VERSION 5.7 ;
BUSBITCHARS "[]" ;
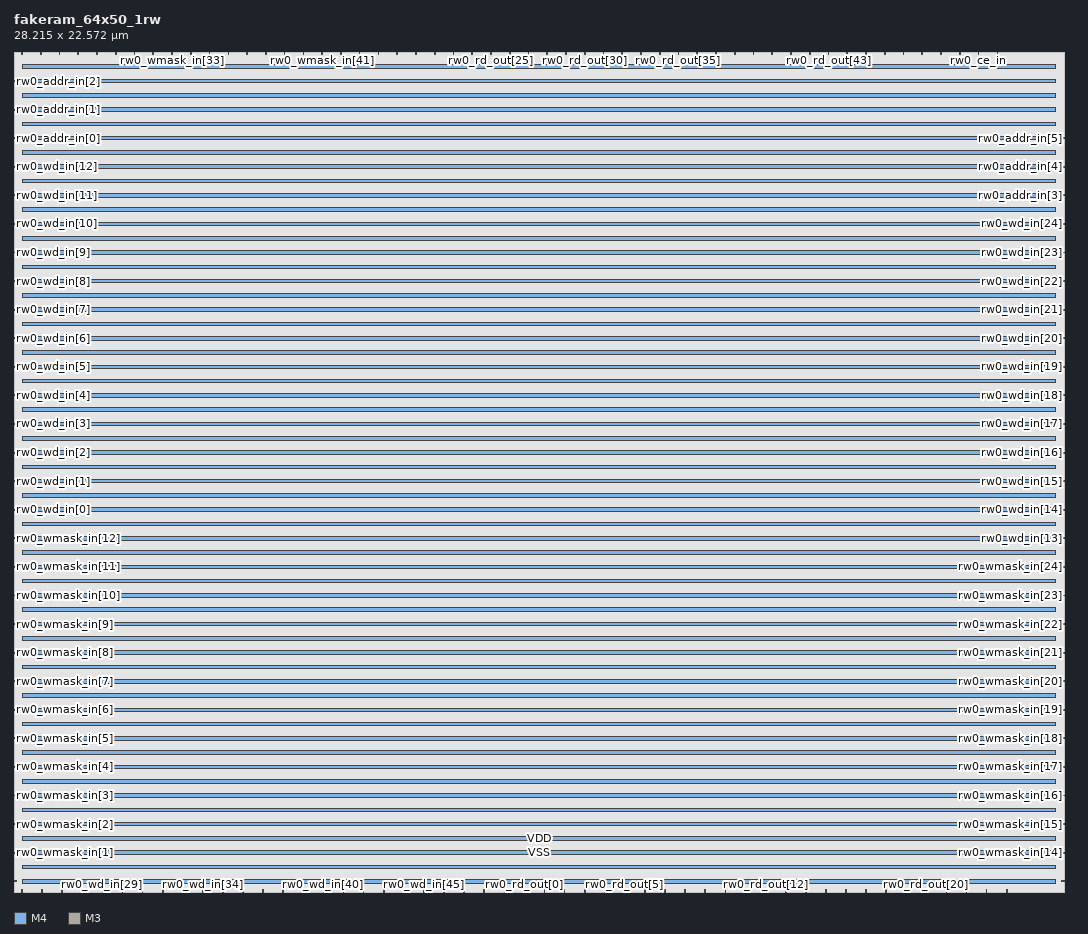
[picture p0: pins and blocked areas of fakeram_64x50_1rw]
MACRO fakeram_64x50_1rw
  FOREIGN fakeram_64x50_1rw 0 0 ;
  SYMMETRY X Y R90 ;
  SIZE 28.215 BY 22.572 ;
  CLASS BLOCK ;
  PIN rw0_wmask_in[0]
    DIRECTION INPUT ;
    USE SIGNAL ;
    SHAPE ABUTMENT ;
    PORT
      LAYER M4 ;
      RECT 0.000 0.276 0.072 0.300 ;
    END
  END rw0_wmask_in[0]
  PIN rw0_wmask_in[1]
    DIRECTION INPUT ;
    USE SIGNAL ;
    SHAPE ABUTMENT ;
    PORT
      LAYER M4 ;
      RECT 0.000 1.044 0.072 1.068 ;
    END
  END rw0_wmask_in[1]
  PIN rw0_wmask_in[2]
    DIRECTION INPUT ;
    USE SIGNAL ;
    SHAPE ABUTMENT ;
    PORT
      LAYER M4 ;
      RECT 0.000 1.812 0.072 1.836 ;
    END
  END rw0_wmask_in[2]
  PIN rw0_wmask_in[3]
    DIRECTION INPUT ;
    USE SIGNAL ;
    SHAPE ABUTMENT ;
    PORT
      LAYER M4 ;
      RECT 0.000 2.580 0.072 2.604 ;
    END
  END rw0_wmask_in[3]
  PIN rw0_wmask_in[4]
    DIRECTION INPUT ;
    USE SIGNAL ;
    SHAPE ABUTMENT ;
    PORT
      LAYER M4 ;
      RECT 0.000 3.348 0.072 3.372 ;
    END
  END rw0_wmask_in[4]
  PIN rw0_wmask_in[5]
    DIRECTION INPUT ;
    USE SIGNAL ;
    SHAPE ABUTMENT ;
    PORT
      LAYER M4 ;
      RECT 0.000 4.116 0.072 4.140 ;
    END
  END rw0_wmask_in[5]
  PIN rw0_wmask_in[6]
    DIRECTION INPUT ;
    USE SIGNAL ;
    SHAPE ABUTMENT ;
    PORT
      LAYER M4 ;
      RECT 0.000 4.884 0.072 4.908 ;
    END
  END rw0_wmask_in[6]
  PIN rw0_wmask_in[7]
    DIRECTION INPUT ;
    USE SIGNAL ;
    SHAPE ABUTMENT ;
    PORT
      LAYER M4 ;
      RECT 0.000 5.652 0.072 5.676 ;
    END
  END rw0_wmask_in[7]
  PIN rw0_wmask_in[8]
    DIRECTION INPUT ;
    USE SIGNAL ;
    SHAPE ABUTMENT ;
    PORT
      LAYER M4 ;
      RECT 0.000 6.420 0.072 6.444 ;
    END
  END rw0_wmask_in[8]
  PIN rw0_wmask_in[9]
    DIRECTION INPUT ;
    USE SIGNAL ;
    SHAPE ABUTMENT ;
    PORT
      LAYER M4 ;
      RECT 0.000 7.188 0.072 7.212 ;
    END
  END rw0_wmask_in[9]
  PIN rw0_wmask_in[10]
    DIRECTION INPUT ;
    USE SIGNAL ;
    SHAPE ABUTMENT ;
    PORT
      LAYER M4 ;
      RECT 0.000 7.956 0.072 7.980 ;
    END
  END rw0_wmask_in[10]
  PIN rw0_wmask_in[11]
    DIRECTION INPUT ;
    USE SIGNAL ;
    SHAPE ABUTMENT ;
    PORT
      LAYER M4 ;
      RECT 0.000 8.724 0.072 8.748 ;
    END
  END rw0_wmask_in[11]
  PIN rw0_wmask_in[12]
    DIRECTION INPUT ;
    USE SIGNAL ;
    SHAPE ABUTMENT ;
    PORT
      LAYER M4 ;
      RECT 0.000 9.492 0.072 9.516 ;
    END
  END rw0_wmask_in[12]
  PIN rw0_wmask_in[13]
    DIRECTION INPUT ;
    USE SIGNAL ;
    SHAPE ABUTMENT ;
    PORT
      LAYER M4 ;
      RECT 28.143 0.276 28.215 0.300 ;
    END
  END rw0_wmask_in[13]
  PIN rw0_wmask_in[14]
    DIRECTION INPUT ;
    USE SIGNAL ;
    SHAPE ABUTMENT ;
    PORT
      LAYER M4 ;
      RECT 28.143 1.044 28.215 1.068 ;
    END
  END rw0_wmask_in[14]
  PIN rw0_wmask_in[15]
    DIRECTION INPUT ;
    USE SIGNAL ;
    SHAPE ABUTMENT ;
    PORT
      LAYER M4 ;
      RECT 28.143 1.812 28.215 1.836 ;
    END
  END rw0_wmask_in[15]
  PIN rw0_wmask_in[16]
    DIRECTION INPUT ;
    USE SIGNAL ;
    SHAPE ABUTMENT ;
    PORT
      LAYER M4 ;
      RECT 28.143 2.580 28.215 2.604 ;
    END
  END rw0_wmask_in[16]
  PIN rw0_wmask_in[17]
    DIRECTION INPUT ;
    USE SIGNAL ;
    SHAPE ABUTMENT ;
    PORT
      LAYER M4 ;
      RECT 28.143 3.348 28.215 3.372 ;
    END
  END rw0_wmask_in[17]
  PIN rw0_wmask_in[18]
    DIRECTION INPUT ;
    USE SIGNAL ;
    SHAPE ABUTMENT ;
    PORT
      LAYER M4 ;
      RECT 28.143 4.116 28.215 4.140 ;
    END
  END rw0_wmask_in[18]
  PIN rw0_wmask_in[19]
    DIRECTION INPUT ;
    USE SIGNAL ;
    SHAPE ABUTMENT ;
    PORT
      LAYER M4 ;
      RECT 28.143 4.884 28.215 4.908 ;
    END
  END rw0_wmask_in[19]
  PIN rw0_wmask_in[20]
    DIRECTION INPUT ;
    USE SIGNAL ;
    SHAPE ABUTMENT ;
    PORT
      LAYER M4 ;
      RECT 28.143 5.652 28.215 5.676 ;
    END
  END rw0_wmask_in[20]
  PIN rw0_wmask_in[21]
    DIRECTION INPUT ;
    USE SIGNAL ;
    SHAPE ABUTMENT ;
    PORT
      LAYER M4 ;
      RECT 28.143 6.420 28.215 6.444 ;
    END
  END rw0_wmask_in[21]
  PIN rw0_wmask_in[22]
    DIRECTION INPUT ;
    USE SIGNAL ;
    SHAPE ABUTMENT ;
    PORT
      LAYER M4 ;
      RECT 28.143 7.188 28.215 7.212 ;
    END
  END rw0_wmask_in[22]
  PIN rw0_wmask_in[23]
    DIRECTION INPUT ;
    USE SIGNAL ;
    SHAPE ABUTMENT ;
    PORT
      LAYER M4 ;
      RECT 28.143 7.956 28.215 7.980 ;
    END
  END rw0_wmask_in[23]
  PIN rw0_wmask_in[24]
    DIRECTION INPUT ;
    USE SIGNAL ;
    SHAPE ABUTMENT ;
    PORT
      LAYER M4 ;
      RECT 28.143 8.724 28.215 8.748 ;
    END
  END rw0_wmask_in[24]
  PIN rw0_wmask_in[25]
    DIRECTION INPUT ;
    USE SIGNAL ;
    SHAPE ABUTMENT ;
    PORT
      LAYER M3 ;
      RECT 0.207 22.518 0.225 22.572 ;
    END
  END rw0_wmask_in[25]
  PIN rw0_wmask_in[26]
    DIRECTION INPUT ;
    USE SIGNAL ;
    SHAPE ABUTMENT ;
    PORT
      LAYER M3 ;
      RECT 0.711 22.518 0.729 22.572 ;
    END
  END rw0_wmask_in[26]
  PIN rw0_wmask_in[27]
    DIRECTION INPUT ;
    USE SIGNAL ;
    SHAPE ABUTMENT ;
    PORT
      LAYER M3 ;
      RECT 1.215 22.518 1.233 22.572 ;
    END
  END rw0_wmask_in[27]
  PIN rw0_wmask_in[28]
    DIRECTION INPUT ;
    USE SIGNAL ;
    SHAPE ABUTMENT ;
    PORT
      LAYER M3 ;
      RECT 1.719 22.518 1.737 22.572 ;
    END
  END rw0_wmask_in[28]
  PIN rw0_wmask_in[29]
    DIRECTION INPUT ;
    USE SIGNAL ;
    SHAPE ABUTMENT ;
    PORT
      LAYER M3 ;
      RECT 2.223 22.518 2.241 22.572 ;
    END
  END rw0_wmask_in[29]
  PIN rw0_wmask_in[30]
    DIRECTION INPUT ;
    USE SIGNAL ;
    SHAPE ABUTMENT ;
    PORT
      LAYER M3 ;
      RECT 2.727 22.518 2.745 22.572 ;
    END
  END rw0_wmask_in[30]
  PIN rw0_wmask_in[31]
    DIRECTION INPUT ;
    USE SIGNAL ;
    SHAPE ABUTMENT ;
    PORT
      LAYER M3 ;
      RECT 3.231 22.518 3.249 22.572 ;
    END
  END rw0_wmask_in[31]
  PIN rw0_wmask_in[32]
    DIRECTION INPUT ;
    USE SIGNAL ;
    SHAPE ABUTMENT ;
    PORT
      LAYER M3 ;
      RECT 3.735 22.518 3.753 22.572 ;
    END
  END rw0_wmask_in[32]
  PIN rw0_wmask_in[33]
    DIRECTION INPUT ;
    USE SIGNAL ;
    SHAPE ABUTMENT ;
    PORT
      LAYER M3 ;
      RECT 4.239 22.518 4.257 22.572 ;
    END
  END rw0_wmask_in[33]
  PIN rw0_wmask_in[34]
    DIRECTION INPUT ;
    USE SIGNAL ;
    SHAPE ABUTMENT ;
    PORT
      LAYER M3 ;
      RECT 4.743 22.518 4.761 22.572 ;
    END
  END rw0_wmask_in[34]
  PIN rw0_wmask_in[35]
    DIRECTION INPUT ;
    USE SIGNAL ;
    SHAPE ABUTMENT ;
    PORT
      LAYER M3 ;
      RECT 5.247 22.518 5.265 22.572 ;
    END
  END rw0_wmask_in[35]
  PIN rw0_wmask_in[36]
    DIRECTION INPUT ;
    USE SIGNAL ;
    SHAPE ABUTMENT ;
    PORT
      LAYER M3 ;
      RECT 5.751 22.518 5.769 22.572 ;
    END
  END rw0_wmask_in[36]
  PIN rw0_wmask_in[37]
    DIRECTION INPUT ;
    USE SIGNAL ;
    SHAPE ABUTMENT ;
    PORT
      LAYER M3 ;
      RECT 6.255 22.518 6.273 22.572 ;
    END
  END rw0_wmask_in[37]
  PIN rw0_wmask_in[38]
    DIRECTION INPUT ;
    USE SIGNAL ;
    SHAPE ABUTMENT ;
    PORT
      LAYER M3 ;
      RECT 6.759 22.518 6.777 22.572 ;
    END
  END rw0_wmask_in[38]
  PIN rw0_wmask_in[39]
    DIRECTION INPUT ;
    USE SIGNAL ;
    SHAPE ABUTMENT ;
    PORT
      LAYER M3 ;
      RECT 7.263 22.518 7.281 22.572 ;
    END
  END rw0_wmask_in[39]
  PIN rw0_wmask_in[40]
    DIRECTION INPUT ;
    USE SIGNAL ;
    SHAPE ABUTMENT ;
    PORT
      LAYER M3 ;
      RECT 7.767 22.518 7.785 22.572 ;
    END
  END rw0_wmask_in[40]
  PIN rw0_wmask_in[41]
    DIRECTION INPUT ;
    USE SIGNAL ;
    SHAPE ABUTMENT ;
    PORT
      LAYER M3 ;
      RECT 8.271 22.518 8.289 22.572 ;
    END
  END rw0_wmask_in[41]
  PIN rw0_wmask_in[42]
    DIRECTION INPUT ;
    USE SIGNAL ;
    SHAPE ABUTMENT ;
    PORT
      LAYER M3 ;
      RECT 8.775 22.518 8.793 22.572 ;
    END
  END rw0_wmask_in[42]
  PIN rw0_wmask_in[43]
    DIRECTION INPUT ;
    USE SIGNAL ;
    SHAPE ABUTMENT ;
    PORT
      LAYER M3 ;
      RECT 9.279 22.518 9.297 22.572 ;
    END
  END rw0_wmask_in[43]
  PIN rw0_wmask_in[44]
    DIRECTION INPUT ;
    USE SIGNAL ;
    SHAPE ABUTMENT ;
    PORT
      LAYER M3 ;
      RECT 9.783 22.518 9.801 22.572 ;
    END
  END rw0_wmask_in[44]
  PIN rw0_wmask_in[45]
    DIRECTION INPUT ;
    USE SIGNAL ;
    SHAPE ABUTMENT ;
    PORT
      LAYER M3 ;
      RECT 10.287 22.518 10.305 22.572 ;
    END
  END rw0_wmask_in[45]
  PIN rw0_wmask_in[46]
    DIRECTION INPUT ;
    USE SIGNAL ;
    SHAPE ABUTMENT ;
    PORT
      LAYER M3 ;
      RECT 10.791 22.518 10.809 22.572 ;
    END
  END rw0_wmask_in[46]
  PIN rw0_wmask_in[47]
    DIRECTION INPUT ;
    USE SIGNAL ;
    SHAPE ABUTMENT ;
    PORT
      LAYER M3 ;
      RECT 11.295 22.518 11.313 22.572 ;
    END
  END rw0_wmask_in[47]
  PIN rw0_wmask_in[48]
    DIRECTION INPUT ;
    USE SIGNAL ;
    SHAPE ABUTMENT ;
    PORT
      LAYER M3 ;
      RECT 11.799 22.518 11.817 22.572 ;
    END
  END rw0_wmask_in[48]
  PIN rw0_wmask_in[49]
    DIRECTION INPUT ;
    USE SIGNAL ;
    SHAPE ABUTMENT ;
    PORT
      LAYER M3 ;
      RECT 12.303 22.518 12.321 22.572 ;
    END
  END rw0_wmask_in[49]
  PIN rw0_wd_in[0]
    DIRECTION INPUT ;
    USE SIGNAL ;
    SHAPE ABUTMENT ;
    PORT
      LAYER M4 ;
      RECT 0.000 10.260 0.072 10.284 ;
    END
  END rw0_wd_in[0]
  PIN rw0_wd_in[1]
    DIRECTION INPUT ;
    USE SIGNAL ;
    SHAPE ABUTMENT ;
    PORT
      LAYER M4 ;
      RECT 0.000 11.028 0.072 11.052 ;
    END
  END rw0_wd_in[1]
  PIN rw0_wd_in[2]
    DIRECTION INPUT ;
    USE SIGNAL ;
    SHAPE ABUTMENT ;
    PORT
      LAYER M4 ;
      RECT 0.000 11.796 0.072 11.820 ;
    END
  END rw0_wd_in[2]
  PIN rw0_wd_in[3]
    DIRECTION INPUT ;
    USE SIGNAL ;
    SHAPE ABUTMENT ;
    PORT
      LAYER M4 ;
      RECT 0.000 12.564 0.072 12.588 ;
    END
  END rw0_wd_in[3]
  PIN rw0_wd_in[4]
    DIRECTION INPUT ;
    USE SIGNAL ;
    SHAPE ABUTMENT ;
    PORT
      LAYER M4 ;
      RECT 0.000 13.332 0.072 13.356 ;
    END
  END rw0_wd_in[4]
  PIN rw0_wd_in[5]
    DIRECTION INPUT ;
    USE SIGNAL ;
    SHAPE ABUTMENT ;
    PORT
      LAYER M4 ;
      RECT 0.000 14.100 0.072 14.124 ;
    END
  END rw0_wd_in[5]
  PIN rw0_wd_in[6]
    DIRECTION INPUT ;
    USE SIGNAL ;
    SHAPE ABUTMENT ;
    PORT
      LAYER M4 ;
      RECT 0.000 14.868 0.072 14.892 ;
    END
  END rw0_wd_in[6]
  PIN rw0_wd_in[7]
    DIRECTION INPUT ;
    USE SIGNAL ;
    SHAPE ABUTMENT ;
    PORT
      LAYER M4 ;
      RECT 0.000 15.636 0.072 15.660 ;
    END
  END rw0_wd_in[7]
  PIN rw0_wd_in[8]
    DIRECTION INPUT ;
    USE SIGNAL ;
    SHAPE ABUTMENT ;
    PORT
      LAYER M4 ;
      RECT 0.000 16.404 0.072 16.428 ;
    END
  END rw0_wd_in[8]
  PIN rw0_wd_in[9]
    DIRECTION INPUT ;
    USE SIGNAL ;
    SHAPE ABUTMENT ;
    PORT
      LAYER M4 ;
      RECT 0.000 17.172 0.072 17.196 ;
    END
  END rw0_wd_in[9]
  PIN rw0_wd_in[10]
    DIRECTION INPUT ;
    USE SIGNAL ;
    SHAPE ABUTMENT ;
    PORT
      LAYER M4 ;
      RECT 0.000 17.940 0.072 17.964 ;
    END
  END rw0_wd_in[10]
  PIN rw0_wd_in[11]
    DIRECTION INPUT ;
    USE SIGNAL ;
    SHAPE ABUTMENT ;
    PORT
      LAYER M4 ;
      RECT 0.000 18.708 0.072 18.732 ;
    END
  END rw0_wd_in[11]
  PIN rw0_wd_in[12]
    DIRECTION INPUT ;
    USE SIGNAL ;
    SHAPE ABUTMENT ;
    PORT
      LAYER M4 ;
      RECT 0.000 19.476 0.072 19.500 ;
    END
  END rw0_wd_in[12]
  PIN rw0_wd_in[13]
    DIRECTION INPUT ;
    USE SIGNAL ;
    SHAPE ABUTMENT ;
    PORT
      LAYER M4 ;
      RECT 28.143 9.492 28.215 9.516 ;
    END
  END rw0_wd_in[13]
  PIN rw0_wd_in[14]
    DIRECTION INPUT ;
    USE SIGNAL ;
    SHAPE ABUTMENT ;
    PORT
      LAYER M4 ;
      RECT 28.143 10.260 28.215 10.284 ;
    END
  END rw0_wd_in[14]
  PIN rw0_wd_in[15]
    DIRECTION INPUT ;
    USE SIGNAL ;
    SHAPE ABUTMENT ;
    PORT
      LAYER M4 ;
      RECT 28.143 11.028 28.215 11.052 ;
    END
  END rw0_wd_in[15]
  PIN rw0_wd_in[16]
    DIRECTION INPUT ;
    USE SIGNAL ;
    SHAPE ABUTMENT ;
    PORT
      LAYER M4 ;
      RECT 28.143 11.796 28.215 11.820 ;
    END
  END rw0_wd_in[16]
  PIN rw0_wd_in[17]
    DIRECTION INPUT ;
    USE SIGNAL ;
    SHAPE ABUTMENT ;
    PORT
      LAYER M4 ;
      RECT 28.143 12.564 28.215 12.588 ;
    END
  END rw0_wd_in[17]
  PIN rw0_wd_in[18]
    DIRECTION INPUT ;
    USE SIGNAL ;
    SHAPE ABUTMENT ;
    PORT
      LAYER M4 ;
      RECT 28.143 13.332 28.215 13.356 ;
    END
  END rw0_wd_in[18]
  PIN rw0_wd_in[19]
    DIRECTION INPUT ;
    USE SIGNAL ;
    SHAPE ABUTMENT ;
    PORT
      LAYER M4 ;
      RECT 28.143 14.100 28.215 14.124 ;
    END
  END rw0_wd_in[19]
  PIN rw0_wd_in[20]
    DIRECTION INPUT ;
    USE SIGNAL ;
    SHAPE ABUTMENT ;
    PORT
      LAYER M4 ;
      RECT 28.143 14.868 28.215 14.892 ;
    END
  END rw0_wd_in[20]
  PIN rw0_wd_in[21]
    DIRECTION INPUT ;
    USE SIGNAL ;
    SHAPE ABUTMENT ;
    PORT
      LAYER M4 ;
      RECT 28.143 15.636 28.215 15.660 ;
    END
  END rw0_wd_in[21]
  PIN rw0_wd_in[22]
    DIRECTION INPUT ;
    USE SIGNAL ;
    SHAPE ABUTMENT ;
    PORT
      LAYER M4 ;
      RECT 28.143 16.404 28.215 16.428 ;
    END
  END rw0_wd_in[22]
  PIN rw0_wd_in[23]
    DIRECTION INPUT ;
    USE SIGNAL ;
    SHAPE ABUTMENT ;
    PORT
      LAYER M4 ;
      RECT 28.143 17.172 28.215 17.196 ;
    END
  END rw0_wd_in[23]
  PIN rw0_wd_in[24]
    DIRECTION INPUT ;
    USE SIGNAL ;
    SHAPE ABUTMENT ;
    PORT
      LAYER M4 ;
      RECT 28.143 17.940 28.215 17.964 ;
    END
  END rw0_wd_in[24]
  PIN rw0_wd_in[25]
    DIRECTION INPUT ;
    USE SIGNAL ;
    SHAPE ABUTMENT ;
    PORT
      LAYER M3 ;
      RECT 0.207 0.000 0.225 0.054 ;
    END
  END rw0_wd_in[25]
  PIN rw0_wd_in[26]
    DIRECTION INPUT ;
    USE SIGNAL ;
    SHAPE ABUTMENT ;
    PORT
      LAYER M3 ;
      RECT 0.747 0.000 0.765 0.054 ;
    END
  END rw0_wd_in[26]
  PIN rw0_wd_in[27]
    DIRECTION INPUT ;
    USE SIGNAL ;
    SHAPE ABUTMENT ;
    PORT
      LAYER M3 ;
      RECT 1.287 0.000 1.305 0.054 ;
    END
  END rw0_wd_in[27]
  PIN rw0_wd_in[28]
    DIRECTION INPUT ;
    USE SIGNAL ;
    SHAPE ABUTMENT ;
    PORT
      LAYER M3 ;
      RECT 1.827 0.000 1.845 0.054 ;
    END
  END rw0_wd_in[28]
  PIN rw0_wd_in[29]
    DIRECTION INPUT ;
    USE SIGNAL ;
    SHAPE ABUTMENT ;
    PORT
      LAYER M3 ;
      RECT 2.367 0.000 2.385 0.054 ;
    END
  END rw0_wd_in[29]
  PIN rw0_wd_in[30]
    DIRECTION INPUT ;
    USE SIGNAL ;
    SHAPE ABUTMENT ;
    PORT
      LAYER M3 ;
      RECT 2.907 0.000 2.925 0.054 ;
    END
  END rw0_wd_in[30]
  PIN rw0_wd_in[31]
    DIRECTION INPUT ;
    USE SIGNAL ;
    SHAPE ABUTMENT ;
    PORT
      LAYER M3 ;
      RECT 3.447 0.000 3.465 0.054 ;
    END
  END rw0_wd_in[31]
  PIN rw0_wd_in[32]
    DIRECTION INPUT ;
    USE SIGNAL ;
    SHAPE ABUTMENT ;
    PORT
      LAYER M3 ;
      RECT 3.987 0.000 4.005 0.054 ;
    END
  END rw0_wd_in[32]
  PIN rw0_wd_in[33]
    DIRECTION INPUT ;
    USE SIGNAL ;
    SHAPE ABUTMENT ;
    PORT
      LAYER M3 ;
      RECT 4.527 0.000 4.545 0.054 ;
    END
  END rw0_wd_in[33]
  PIN rw0_wd_in[34]
    DIRECTION INPUT ;
    USE SIGNAL ;
    SHAPE ABUTMENT ;
    PORT
      LAYER M3 ;
      RECT 5.067 0.000 5.085 0.054 ;
    END
  END rw0_wd_in[34]
  PIN rw0_wd_in[35]
    DIRECTION INPUT ;
    USE SIGNAL ;
    SHAPE ABUTMENT ;
    PORT
      LAYER M3 ;
      RECT 5.607 0.000 5.625 0.054 ;
    END
  END rw0_wd_in[35]
  PIN rw0_wd_in[36]
    DIRECTION INPUT ;
    USE SIGNAL ;
    SHAPE ABUTMENT ;
    PORT
      LAYER M3 ;
      RECT 6.147 0.000 6.165 0.054 ;
    END
  END rw0_wd_in[36]
  PIN rw0_wd_in[37]
    DIRECTION INPUT ;
    USE SIGNAL ;
    SHAPE ABUTMENT ;
    PORT
      LAYER M3 ;
      RECT 6.687 0.000 6.705 0.054 ;
    END
  END rw0_wd_in[37]
  PIN rw0_wd_in[38]
    DIRECTION INPUT ;
    USE SIGNAL ;
    SHAPE ABUTMENT ;
    PORT
      LAYER M3 ;
      RECT 7.227 0.000 7.245 0.054 ;
    END
  END rw0_wd_in[38]
  PIN rw0_wd_in[39]
    DIRECTION INPUT ;
    USE SIGNAL ;
    SHAPE ABUTMENT ;
    PORT
      LAYER M3 ;
      RECT 7.767 0.000 7.785 0.054 ;
    END
  END rw0_wd_in[39]
  PIN rw0_wd_in[40]
    DIRECTION INPUT ;
    USE SIGNAL ;
    SHAPE ABUTMENT ;
    PORT
      LAYER M3 ;
      RECT 8.307 0.000 8.325 0.054 ;
    END
  END rw0_wd_in[40]
  PIN rw0_wd_in[41]
    DIRECTION INPUT ;
    USE SIGNAL ;
    SHAPE ABUTMENT ;
    PORT
      LAYER M3 ;
      RECT 8.847 0.000 8.865 0.054 ;
    END
  END rw0_wd_in[41]
  PIN rw0_wd_in[42]
    DIRECTION INPUT ;
    USE SIGNAL ;
    SHAPE ABUTMENT ;
    PORT
      LAYER M3 ;
      RECT 9.387 0.000 9.405 0.054 ;
    END
  END rw0_wd_in[42]
  PIN rw0_wd_in[43]
    DIRECTION INPUT ;
    USE SIGNAL ;
    SHAPE ABUTMENT ;
    PORT
      LAYER M3 ;
      RECT 9.927 0.000 9.945 0.054 ;
    END
  END rw0_wd_in[43]
  PIN rw0_wd_in[44]
    DIRECTION INPUT ;
    USE SIGNAL ;
    SHAPE ABUTMENT ;
    PORT
      LAYER M3 ;
      RECT 10.467 0.000 10.485 0.054 ;
    END
  END rw0_wd_in[44]
  PIN rw0_wd_in[45]
    DIRECTION INPUT ;
    USE SIGNAL ;
    SHAPE ABUTMENT ;
    PORT
      LAYER M3 ;
      RECT 11.007 0.000 11.025 0.054 ;
    END
  END rw0_wd_in[45]
  PIN rw0_wd_in[46]
    DIRECTION INPUT ;
    USE SIGNAL ;
    SHAPE ABUTMENT ;
    PORT
      LAYER M3 ;
      RECT 11.547 0.000 11.565 0.054 ;
    END
  END rw0_wd_in[46]
  PIN rw0_wd_in[47]
    DIRECTION INPUT ;
    USE SIGNAL ;
    SHAPE ABUTMENT ;
    PORT
      LAYER M3 ;
      RECT 12.087 0.000 12.105 0.054 ;
    END
  END rw0_wd_in[47]
  PIN rw0_wd_in[48]
    DIRECTION INPUT ;
    USE SIGNAL ;
    SHAPE ABUTMENT ;
    PORT
      LAYER M3 ;
      RECT 12.627 0.000 12.645 0.054 ;
    END
  END rw0_wd_in[48]
  PIN rw0_wd_in[49]
    DIRECTION INPUT ;
    USE SIGNAL ;
    SHAPE ABUTMENT ;
    PORT
      LAYER M3 ;
      RECT 13.167 0.000 13.185 0.054 ;
    END
  END rw0_wd_in[49]
  PIN rw0_rd_out[0]
    DIRECTION OUTPUT ;
    USE SIGNAL ;
    SHAPE ABUTMENT ;
    PORT
      LAYER M3 ;
      RECT 13.707 0.000 13.725 0.054 ;
    END
  END rw0_rd_out[0]
  PIN rw0_rd_out[1]
    DIRECTION OUTPUT ;
    USE SIGNAL ;
    SHAPE ABUTMENT ;
    PORT
      LAYER M3 ;
      RECT 14.247 0.000 14.265 0.054 ;
    END
  END rw0_rd_out[1]
  PIN rw0_rd_out[2]
    DIRECTION OUTPUT ;
    USE SIGNAL ;
    SHAPE ABUTMENT ;
    PORT
      LAYER M3 ;
      RECT 14.787 0.000 14.805 0.054 ;
    END
  END rw0_rd_out[2]
  PIN rw0_rd_out[3]
    DIRECTION OUTPUT ;
    USE SIGNAL ;
    SHAPE ABUTMENT ;
    PORT
      LAYER M3 ;
      RECT 15.327 0.000 15.345 0.054 ;
    END
  END rw0_rd_out[3]
  PIN rw0_rd_out[4]
    DIRECTION OUTPUT ;
    USE SIGNAL ;
    SHAPE ABUTMENT ;
    PORT
      LAYER M3 ;
      RECT 15.867 0.000 15.885 0.054 ;
    END
  END rw0_rd_out[4]
  PIN rw0_rd_out[5]
    DIRECTION OUTPUT ;
    USE SIGNAL ;
    SHAPE ABUTMENT ;
    PORT
      LAYER M3 ;
      RECT 16.407 0.000 16.425 0.054 ;
    END
  END rw0_rd_out[5]
  PIN rw0_rd_out[6]
    DIRECTION OUTPUT ;
    USE SIGNAL ;
    SHAPE ABUTMENT ;
    PORT
      LAYER M3 ;
      RECT 16.947 0.000 16.965 0.054 ;
    END
  END rw0_rd_out[6]
  PIN rw0_rd_out[7]
    DIRECTION OUTPUT ;
    USE SIGNAL ;
    SHAPE ABUTMENT ;
    PORT
      LAYER M3 ;
      RECT 17.487 0.000 17.505 0.054 ;
    END
  END rw0_rd_out[7]
  PIN rw0_rd_out[8]
    DIRECTION OUTPUT ;
    USE SIGNAL ;
    SHAPE ABUTMENT ;
    PORT
      LAYER M3 ;
      RECT 18.027 0.000 18.045 0.054 ;
    END
  END rw0_rd_out[8]
  PIN rw0_rd_out[9]
    DIRECTION OUTPUT ;
    USE SIGNAL ;
    SHAPE ABUTMENT ;
    PORT
      LAYER M3 ;
      RECT 18.567 0.000 18.585 0.054 ;
    END
  END rw0_rd_out[9]
  PIN rw0_rd_out[10]
    DIRECTION OUTPUT ;
    USE SIGNAL ;
    SHAPE ABUTMENT ;
    PORT
      LAYER M3 ;
      RECT 19.107 0.000 19.125 0.054 ;
    END
  END rw0_rd_out[10]
  PIN rw0_rd_out[11]
    DIRECTION OUTPUT ;
    USE SIGNAL ;
    SHAPE ABUTMENT ;
    PORT
      LAYER M3 ;
      RECT 19.647 0.000 19.665 0.054 ;
    END
  END rw0_rd_out[11]
  PIN rw0_rd_out[12]
    DIRECTION OUTPUT ;
    USE SIGNAL ;
    SHAPE ABUTMENT ;
    PORT
      LAYER M3 ;
      RECT 20.187 0.000 20.205 0.054 ;
    END
  END rw0_rd_out[12]
  PIN rw0_rd_out[13]
    DIRECTION OUTPUT ;
    USE SIGNAL ;
    SHAPE ABUTMENT ;
    PORT
      LAYER M3 ;
      RECT 20.727 0.000 20.745 0.054 ;
    END
  END rw0_rd_out[13]
  PIN rw0_rd_out[14]
    DIRECTION OUTPUT ;
    USE SIGNAL ;
    SHAPE ABUTMENT ;
    PORT
      LAYER M3 ;
      RECT 21.267 0.000 21.285 0.054 ;
    END
  END rw0_rd_out[14]
  PIN rw0_rd_out[15]
    DIRECTION OUTPUT ;
    USE SIGNAL ;
    SHAPE ABUTMENT ;
    PORT
      LAYER M3 ;
      RECT 21.807 0.000 21.825 0.054 ;
    END
  END rw0_rd_out[15]
  PIN rw0_rd_out[16]
    DIRECTION OUTPUT ;
    USE SIGNAL ;
    SHAPE ABUTMENT ;
    PORT
      LAYER M3 ;
      RECT 22.347 0.000 22.365 0.054 ;
    END
  END rw0_rd_out[16]
  PIN rw0_rd_out[17]
    DIRECTION OUTPUT ;
    USE SIGNAL ;
    SHAPE ABUTMENT ;
    PORT
      LAYER M3 ;
      RECT 22.887 0.000 22.905 0.054 ;
    END
  END rw0_rd_out[17]
  PIN rw0_rd_out[18]
    DIRECTION OUTPUT ;
    USE SIGNAL ;
    SHAPE ABUTMENT ;
    PORT
      LAYER M3 ;
      RECT 23.427 0.000 23.445 0.054 ;
    END
  END rw0_rd_out[18]
  PIN rw0_rd_out[19]
    DIRECTION OUTPUT ;
    USE SIGNAL ;
    SHAPE ABUTMENT ;
    PORT
      LAYER M3 ;
      RECT 23.967 0.000 23.985 0.054 ;
    END
  END rw0_rd_out[19]
  PIN rw0_rd_out[20]
    DIRECTION OUTPUT ;
    USE SIGNAL ;
    SHAPE ABUTMENT ;
    PORT
      LAYER M3 ;
      RECT 24.507 0.000 24.525 0.054 ;
    END
  END rw0_rd_out[20]
  PIN rw0_rd_out[21]
    DIRECTION OUTPUT ;
    USE SIGNAL ;
    SHAPE ABUTMENT ;
    PORT
      LAYER M3 ;
      RECT 25.047 0.000 25.065 0.054 ;
    END
  END rw0_rd_out[21]
  PIN rw0_rd_out[22]
    DIRECTION OUTPUT ;
    USE SIGNAL ;
    SHAPE ABUTMENT ;
    PORT
      LAYER M3 ;
      RECT 25.587 0.000 25.605 0.054 ;
    END
  END rw0_rd_out[22]
  PIN rw0_rd_out[23]
    DIRECTION OUTPUT ;
    USE SIGNAL ;
    SHAPE ABUTMENT ;
    PORT
      LAYER M3 ;
      RECT 26.127 0.000 26.145 0.054 ;
    END
  END rw0_rd_out[23]
  PIN rw0_rd_out[24]
    DIRECTION OUTPUT ;
    USE SIGNAL ;
    SHAPE ABUTMENT ;
    PORT
      LAYER M3 ;
      RECT 26.667 0.000 26.685 0.054 ;
    END
  END rw0_rd_out[24]
  PIN rw0_rd_out[25]
    DIRECTION OUTPUT ;
    USE SIGNAL ;
    SHAPE ABUTMENT ;
    PORT
      LAYER M3 ;
      RECT 12.807 22.518 12.825 22.572 ;
    END
  END rw0_rd_out[25]
  PIN rw0_rd_out[26]
    DIRECTION OUTPUT ;
    USE SIGNAL ;
    SHAPE ABUTMENT ;
    PORT
      LAYER M3 ;
      RECT 13.311 22.518 13.329 22.572 ;
    END
  END rw0_rd_out[26]
  PIN rw0_rd_out[27]
    DIRECTION OUTPUT ;
    USE SIGNAL ;
    SHAPE ABUTMENT ;
    PORT
      LAYER M3 ;
      RECT 13.815 22.518 13.833 22.572 ;
    END
  END rw0_rd_out[27]
  PIN rw0_rd_out[28]
    DIRECTION OUTPUT ;
    USE SIGNAL ;
    SHAPE ABUTMENT ;
    PORT
      LAYER M3 ;
      RECT 14.319 22.518 14.337 22.572 ;
    END
  END rw0_rd_out[28]
  PIN rw0_rd_out[29]
    DIRECTION OUTPUT ;
    USE SIGNAL ;
    SHAPE ABUTMENT ;
    PORT
      LAYER M3 ;
      RECT 14.823 22.518 14.841 22.572 ;
    END
  END rw0_rd_out[29]
  PIN rw0_rd_out[30]
    DIRECTION OUTPUT ;
    USE SIGNAL ;
    SHAPE ABUTMENT ;
    PORT
      LAYER M3 ;
      RECT 15.327 22.518 15.345 22.572 ;
    END
  END rw0_rd_out[30]
  PIN rw0_rd_out[31]
    DIRECTION OUTPUT ;
    USE SIGNAL ;
    SHAPE ABUTMENT ;
    PORT
      LAYER M3 ;
      RECT 15.831 22.518 15.849 22.572 ;
    END
  END rw0_rd_out[31]
  PIN rw0_rd_out[32]
    DIRECTION OUTPUT ;
    USE SIGNAL ;
    SHAPE ABUTMENT ;
    PORT
      LAYER M3 ;
      RECT 16.335 22.518 16.353 22.572 ;
    END
  END rw0_rd_out[32]
  PIN rw0_rd_out[33]
    DIRECTION OUTPUT ;
    USE SIGNAL ;
    SHAPE ABUTMENT ;
    PORT
      LAYER M3 ;
      RECT 16.839 22.518 16.857 22.572 ;
    END
  END rw0_rd_out[33]
  PIN rw0_rd_out[34]
    DIRECTION OUTPUT ;
    USE SIGNAL ;
    SHAPE ABUTMENT ;
    PORT
      LAYER M3 ;
      RECT 17.343 22.518 17.361 22.572 ;
    END
  END rw0_rd_out[34]
  PIN rw0_rd_out[35]
    DIRECTION OUTPUT ;
    USE SIGNAL ;
    SHAPE ABUTMENT ;
    PORT
      LAYER M3 ;
      RECT 17.847 22.518 17.865 22.572 ;
    END
  END rw0_rd_out[35]
  PIN rw0_rd_out[36]
    DIRECTION OUTPUT ;
    USE SIGNAL ;
    SHAPE ABUTMENT ;
    PORT
      LAYER M3 ;
      RECT 18.351 22.518 18.369 22.572 ;
    END
  END rw0_rd_out[36]
  PIN rw0_rd_out[37]
    DIRECTION OUTPUT ;
    USE SIGNAL ;
    SHAPE ABUTMENT ;
    PORT
      LAYER M3 ;
      RECT 18.855 22.518 18.873 22.572 ;
    END
  END rw0_rd_out[37]
  PIN rw0_rd_out[38]
    DIRECTION OUTPUT ;
    USE SIGNAL ;
    SHAPE ABUTMENT ;
    PORT
      LAYER M3 ;
      RECT 19.359 22.518 19.377 22.572 ;
    END
  END rw0_rd_out[38]
  PIN rw0_rd_out[39]
    DIRECTION OUTPUT ;
    USE SIGNAL ;
    SHAPE ABUTMENT ;
    PORT
      LAYER M3 ;
      RECT 19.863 22.518 19.881 22.572 ;
    END
  END rw0_rd_out[39]
  PIN rw0_rd_out[40]
    DIRECTION OUTPUT ;
    USE SIGNAL ;
    SHAPE ABUTMENT ;
    PORT
      LAYER M3 ;
      RECT 20.367 22.518 20.385 22.572 ;
    END
  END rw0_rd_out[40]
  PIN rw0_rd_out[41]
    DIRECTION OUTPUT ;
    USE SIGNAL ;
    SHAPE ABUTMENT ;
    PORT
      LAYER M3 ;
      RECT 20.871 22.518 20.889 22.572 ;
    END
  END rw0_rd_out[41]
  PIN rw0_rd_out[42]
    DIRECTION OUTPUT ;
    USE SIGNAL ;
    SHAPE ABUTMENT ;
    PORT
      LAYER M3 ;
      RECT 21.375 22.518 21.393 22.572 ;
    END
  END rw0_rd_out[42]
  PIN rw0_rd_out[43]
    DIRECTION OUTPUT ;
    USE SIGNAL ;
    SHAPE ABUTMENT ;
    PORT
      LAYER M3 ;
      RECT 21.879 22.518 21.897 22.572 ;
    END
  END rw0_rd_out[43]
  PIN rw0_rd_out[44]
    DIRECTION OUTPUT ;
    USE SIGNAL ;
    SHAPE ABUTMENT ;
    PORT
      LAYER M3 ;
      RECT 22.383 22.518 22.401 22.572 ;
    END
  END rw0_rd_out[44]
  PIN rw0_rd_out[45]
    DIRECTION OUTPUT ;
    USE SIGNAL ;
    SHAPE ABUTMENT ;
    PORT
      LAYER M3 ;
      RECT 22.887 22.518 22.905 22.572 ;
    END
  END rw0_rd_out[45]
  PIN rw0_rd_out[46]
    DIRECTION OUTPUT ;
    USE SIGNAL ;
    SHAPE ABUTMENT ;
    PORT
      LAYER M3 ;
      RECT 23.391 22.518 23.409 22.572 ;
    END
  END rw0_rd_out[46]
  PIN rw0_rd_out[47]
    DIRECTION OUTPUT ;
    USE SIGNAL ;
    SHAPE ABUTMENT ;
    PORT
      LAYER M3 ;
      RECT 23.895 22.518 23.913 22.572 ;
    END
  END rw0_rd_out[47]
  PIN rw0_rd_out[48]
    DIRECTION OUTPUT ;
    USE SIGNAL ;
    SHAPE ABUTMENT ;
    PORT
      LAYER M3 ;
      RECT 24.399 22.518 24.417 22.572 ;
    END
  END rw0_rd_out[48]
  PIN rw0_rd_out[49]
    DIRECTION OUTPUT ;
    USE SIGNAL ;
    SHAPE ABUTMENT ;
    PORT
      LAYER M3 ;
      RECT 24.903 22.518 24.921 22.572 ;
    END
  END rw0_rd_out[49]
  PIN rw0_addr_in[0]
    DIRECTION INPUT ;
    USE SIGNAL ;
    SHAPE ABUTMENT ;
    PORT
      LAYER M4 ;
      RECT 0.000 20.244 0.072 20.268 ;
    END
  END rw0_addr_in[0]
  PIN rw0_addr_in[1]
    DIRECTION INPUT ;
    USE SIGNAL ;
    SHAPE ABUTMENT ;
    PORT
      LAYER M4 ;
      RECT 0.000 21.012 0.072 21.036 ;
    END
  END rw0_addr_in[1]
  PIN rw0_addr_in[2]
    DIRECTION INPUT ;
    USE SIGNAL ;
    SHAPE ABUTMENT ;
    PORT
      LAYER M4 ;
      RECT 0.000 21.780 0.072 21.804 ;
    END
  END rw0_addr_in[2]
  PIN rw0_addr_in[3]
    DIRECTION INPUT ;
    USE SIGNAL ;
    SHAPE ABUTMENT ;
    PORT
      LAYER M4 ;
      RECT 28.143 18.708 28.215 18.732 ;
    END
  END rw0_addr_in[3]
  PIN rw0_addr_in[4]
    DIRECTION INPUT ;
    USE SIGNAL ;
    SHAPE ABUTMENT ;
    PORT
      LAYER M4 ;
      RECT 28.143 19.476 28.215 19.500 ;
    END
  END rw0_addr_in[4]
  PIN rw0_addr_in[5]
    DIRECTION INPUT ;
    USE SIGNAL ;
    SHAPE ABUTMENT ;
    PORT
      LAYER M4 ;
      RECT 28.143 20.244 28.215 20.268 ;
    END
  END rw0_addr_in[5]
  PIN rw0_we_in
    DIRECTION INPUT ;
    USE SIGNAL ;
    SHAPE ABUTMENT ;
    PORT
      LAYER M3 ;
      RECT 25.407 22.518 25.425 22.572 ;
    END
  END rw0_we_in
  PIN rw0_ce_in
    DIRECTION INPUT ;
    USE SIGNAL ;
    SHAPE ABUTMENT ;
    PORT
      LAYER M3 ;
      RECT 25.911 22.518 25.929 22.572 ;
    END
  END rw0_ce_in
  PIN rw0_clk
    DIRECTION INPUT ;
    USE SIGNAL ;
    SHAPE ABUTMENT ;
    PORT
      LAYER M3 ;
      RECT 26.415 22.518 26.433 22.572 ;
    END
  END rw0_clk
  PIN VSS
    DIRECTION INOUT ;
    USE GROUND ;
    PORT
      LAYER M4 ;
      RECT 0.216 0.240 27.999 0.336 ;
      RECT 0.216 1.008 27.999 1.104 ;
      RECT 0.216 1.776 27.999 1.872 ;
      RECT 0.216 2.544 27.999 2.640 ;
      RECT 0.216 3.312 27.999 3.408 ;
      RECT 0.216 4.080 27.999 4.176 ;
      RECT 0.216 4.848 27.999 4.944 ;
      RECT 0.216 5.616 27.999 5.712 ;
      RECT 0.216 6.384 27.999 6.480 ;
      RECT 0.216 7.152 27.999 7.248 ;
      RECT 0.216 7.920 27.999 8.016 ;
      RECT 0.216 8.688 27.999 8.784 ;
      RECT 0.216 9.456 27.999 9.552 ;
      RECT 0.216 10.224 27.999 10.320 ;
      RECT 0.216 10.992 27.999 11.088 ;
      RECT 0.216 11.760 27.999 11.856 ;
      RECT 0.216 12.528 27.999 12.624 ;
      RECT 0.216 13.296 27.999 13.392 ;
      RECT 0.216 14.064 27.999 14.160 ;
      RECT 0.216 14.832 27.999 14.928 ;
      RECT 0.216 15.600 27.999 15.696 ;
      RECT 0.216 16.368 27.999 16.464 ;
      RECT 0.216 17.136 27.999 17.232 ;
      RECT 0.216 17.904 27.999 18.000 ;
      RECT 0.216 18.672 27.999 18.768 ;
      RECT 0.216 19.440 27.999 19.536 ;
      RECT 0.216 20.208 27.999 20.304 ;
      RECT 0.216 20.976 27.999 21.072 ;
      RECT 0.216 21.744 27.999 21.840 ;
    END
  END VSS
  PIN VDD
    DIRECTION INOUT ;
    USE POWER ;
    PORT
      LAYER M4 ;
      RECT 0.216 0.624 27.999 0.720 ;
      RECT 0.216 1.392 27.999 1.488 ;
      RECT 0.216 2.160 27.999 2.256 ;
      RECT 0.216 2.928 27.999 3.024 ;
      RECT 0.216 3.696 27.999 3.792 ;
      RECT 0.216 4.464 27.999 4.560 ;
      RECT 0.216 5.232 27.999 5.328 ;
      RECT 0.216 6.000 27.999 6.096 ;
      RECT 0.216 6.768 27.999 6.864 ;
      RECT 0.216 7.536 27.999 7.632 ;
      RECT 0.216 8.304 27.999 8.400 ;
      RECT 0.216 9.072 27.999 9.168 ;
      RECT 0.216 9.840 27.999 9.936 ;
      RECT 0.216 10.608 27.999 10.704 ;
      RECT 0.216 11.376 27.999 11.472 ;
      RECT 0.216 12.144 27.999 12.240 ;
      RECT 0.216 12.912 27.999 13.008 ;
      RECT 0.216 13.680 27.999 13.776 ;
      RECT 0.216 14.448 27.999 14.544 ;
      RECT 0.216 15.216 27.999 15.312 ;
      RECT 0.216 15.984 27.999 16.080 ;
      RECT 0.216 16.752 27.999 16.848 ;
      RECT 0.216 17.520 27.999 17.616 ;
      RECT 0.216 18.288 27.999 18.384 ;
      RECT 0.216 19.056 27.999 19.152 ;
      RECT 0.216 19.824 27.999 19.920 ;
      RECT 0.216 20.592 27.999 20.688 ;
      RECT 0.216 21.360 27.999 21.456 ;
      RECT 0.216 22.128 27.999 22.224 ;
    END
  END VDD
  OBS
    LAYER M1 ;
    RECT 0 0 28.215 22.572 ;
    LAYER M2 ;
    RECT 0 0 28.215 22.572 ;
    LAYER M3 ;
    RECT 0 0 28.215 22.572 ;
    LAYER M4 ;
    RECT 0 0 28.215 22.572 ;
  END
END fakeram_64x50_1rw

END LIBRARY
